VERSION 5.7 ;
  NOWIREEXTENSIONATPIN ON ;
  DIVIDERCHAR "/" ;
  BUSBITCHARS "[]" ;
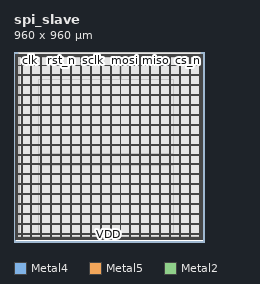
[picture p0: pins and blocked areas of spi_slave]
MACRO spi_slave
  CLASS BLOCK ;
  FOREIGN spi_slave ;
  ORIGIN 0.000 0.000 ;
  SIZE 960.000 BY 960.000 ;
  PIN VDD
    DIRECTION INOUT ;
    USE POWER ;
    PORT
      LAYER Metal4 ;
        RECT 14.160 17.520 19.160 942.880 ;
    END
    PORT
      LAYER Metal4 ;
        RECT 940.680 17.520 945.680 942.880 ;
    END
    PORT
      LAYER Metal5 ;
        RECT 14.160 17.520 945.680 22.520 ;
    END
    PORT
      LAYER Metal5 ;
        RECT 14.160 937.880 945.680 942.880 ;
    END
    PORT
      LAYER Metal4 ;
        RECT 35.680 10.520 37.280 949.880 ;
    END
    PORT
      LAYER Metal4 ;
        RECT 85.680 10.520 87.280 949.880 ;
    END
    PORT
      LAYER Metal4 ;
        RECT 135.680 10.520 137.280 949.880 ;
    END
    PORT
      LAYER Metal4 ;
        RECT 185.680 10.520 187.280 949.880 ;
    END
    PORT
      LAYER Metal4 ;
        RECT 235.680 10.520 237.280 949.880 ;
    END
    PORT
      LAYER Metal4 ;
        RECT 285.680 10.520 287.280 949.880 ;
    END
    PORT
      LAYER Metal4 ;
        RECT 335.680 10.520 337.280 949.880 ;
    END
    PORT
      LAYER Metal4 ;
        RECT 385.680 10.520 387.280 949.880 ;
    END
    PORT
      LAYER Metal4 ;
        RECT 435.680 10.520 437.280 949.880 ;
    END
    PORT
      LAYER Metal4 ;
        RECT 485.680 10.520 487.280 949.880 ;
    END
    PORT
      LAYER Metal4 ;
        RECT 535.680 10.520 537.280 949.880 ;
    END
    PORT
      LAYER Metal4 ;
        RECT 585.680 10.520 587.280 949.880 ;
    END
    PORT
      LAYER Metal4 ;
        RECT 635.680 10.520 637.280 949.880 ;
    END
    PORT
      LAYER Metal4 ;
        RECT 685.680 10.520 687.280 949.880 ;
    END
    PORT
      LAYER Metal4 ;
        RECT 735.680 10.520 737.280 949.880 ;
    END
    PORT
      LAYER Metal4 ;
        RECT 785.680 10.520 787.280 949.880 ;
    END
    PORT
      LAYER Metal4 ;
        RECT 835.680 10.520 837.280 949.880 ;
    END
    PORT
      LAYER Metal4 ;
        RECT 885.680 10.520 887.280 949.880 ;
    END
    PORT
      LAYER Metal4 ;
        RECT 935.680 10.520 937.280 949.880 ;
    END
    PORT
      LAYER Metal5 ;
        RECT 7.160 39.370 952.680 40.970 ;
    END
    PORT
      LAYER Metal5 ;
        RECT 7.160 89.370 952.680 90.970 ;
    END
    PORT
      LAYER Metal5 ;
        RECT 7.160 139.370 952.680 140.970 ;
    END
    PORT
      LAYER Metal5 ;
        RECT 7.160 189.370 952.680 190.970 ;
    END
    PORT
      LAYER Metal5 ;
        RECT 7.160 239.370 952.680 240.970 ;
    END
    PORT
      LAYER Metal5 ;
        RECT 7.160 289.370 952.680 290.970 ;
    END
    PORT
      LAYER Metal5 ;
        RECT 7.160 339.370 952.680 340.970 ;
    END
    PORT
      LAYER Metal5 ;
        RECT 7.160 389.370 952.680 390.970 ;
    END
    PORT
      LAYER Metal5 ;
        RECT 7.160 439.370 952.680 440.970 ;
    END
    PORT
      LAYER Metal5 ;
        RECT 7.160 489.370 952.680 490.970 ;
    END
    PORT
      LAYER Metal5 ;
        RECT 7.160 539.370 952.680 540.970 ;
    END
    PORT
      LAYER Metal5 ;
        RECT 7.160 589.370 952.680 590.970 ;
    END
    PORT
      LAYER Metal5 ;
        RECT 7.160 639.370 952.680 640.970 ;
    END
    PORT
      LAYER Metal5 ;
        RECT 7.160 689.370 952.680 690.970 ;
    END
    PORT
      LAYER Metal5 ;
        RECT 7.160 739.370 952.680 740.970 ;
    END
    PORT
      LAYER Metal5 ;
        RECT 7.160 789.370 952.680 790.970 ;
    END
    PORT
      LAYER Metal5 ;
        RECT 7.160 839.370 952.680 840.970 ;
    END
    PORT
      LAYER Metal5 ;
        RECT 7.160 889.370 952.680 890.970 ;
    END
  END VDD
  PIN VSS
    DIRECTION INOUT ;
    USE GROUND ;
    PORT
      LAYER Metal4 ;
        RECT 7.160 10.520 12.160 949.880 ;
    END
    PORT
      LAYER Metal4 ;
        RECT 947.680 10.520 952.680 949.880 ;
    END
    PORT
      LAYER Metal5 ;
        RECT 7.160 10.520 952.680 15.520 ;
    END
    PORT
      LAYER Metal5 ;
        RECT 7.160 944.880 952.680 949.880 ;
    END
    PORT
      LAYER Metal4 ;
        RECT 38.880 10.520 40.480 949.880 ;
    END
    PORT
      LAYER Metal4 ;
        RECT 88.880 10.520 90.480 949.880 ;
    END
    PORT
      LAYER Metal4 ;
        RECT 138.880 10.520 140.480 949.880 ;
    END
    PORT
      LAYER Metal4 ;
        RECT 188.880 10.520 190.480 949.880 ;
    END
    PORT
      LAYER Metal4 ;
        RECT 238.880 10.520 240.480 949.880 ;
    END
    PORT
      LAYER Metal4 ;
        RECT 288.880 10.520 290.480 949.880 ;
    END
    PORT
      LAYER Metal4 ;
        RECT 338.880 10.520 340.480 949.880 ;
    END
    PORT
      LAYER Metal4 ;
        RECT 388.880 10.520 390.480 949.880 ;
    END
    PORT
      LAYER Metal4 ;
        RECT 438.880 10.520 440.480 949.880 ;
    END
    PORT
      LAYER Metal4 ;
        RECT 488.880 10.520 490.480 949.880 ;
    END
    PORT
      LAYER Metal4 ;
        RECT 538.880 10.520 540.480 949.880 ;
    END
    PORT
      LAYER Metal4 ;
        RECT 588.880 10.520 590.480 949.880 ;
    END
    PORT
      LAYER Metal4 ;
        RECT 638.880 10.520 640.480 949.880 ;
    END
    PORT
      LAYER Metal4 ;
        RECT 688.880 10.520 690.480 949.880 ;
    END
    PORT
      LAYER Metal4 ;
        RECT 738.880 10.520 740.480 949.880 ;
    END
    PORT
      LAYER Metal4 ;
        RECT 788.880 10.520 790.480 949.880 ;
    END
    PORT
      LAYER Metal4 ;
        RECT 838.880 10.520 840.480 949.880 ;
    END
    PORT
      LAYER Metal4 ;
        RECT 888.880 10.520 890.480 949.880 ;
    END
    PORT
      LAYER Metal5 ;
        RECT 7.160 42.570 952.680 44.170 ;
    END
    PORT
      LAYER Metal5 ;
        RECT 7.160 92.570 952.680 94.170 ;
    END
    PORT
      LAYER Metal5 ;
        RECT 7.160 142.570 952.680 144.170 ;
    END
    PORT
      LAYER Metal5 ;
        RECT 7.160 192.570 952.680 194.170 ;
    END
    PORT
      LAYER Metal5 ;
        RECT 7.160 242.570 952.680 244.170 ;
    END
    PORT
      LAYER Metal5 ;
        RECT 7.160 292.570 952.680 294.170 ;
    END
    PORT
      LAYER Metal5 ;
        RECT 7.160 342.570 952.680 344.170 ;
    END
    PORT
      LAYER Metal5 ;
        RECT 7.160 392.570 952.680 394.170 ;
    END
    PORT
      LAYER Metal5 ;
        RECT 7.160 442.570 952.680 444.170 ;
    END
    PORT
      LAYER Metal5 ;
        RECT 7.160 492.570 952.680 494.170 ;
    END
    PORT
      LAYER Metal5 ;
        RECT 7.160 542.570 952.680 544.170 ;
    END
    PORT
      LAYER Metal5 ;
        RECT 7.160 592.570 952.680 594.170 ;
    END
    PORT
      LAYER Metal5 ;
        RECT 7.160 642.570 952.680 644.170 ;
    END
    PORT
      LAYER Metal5 ;
        RECT 7.160 692.570 952.680 694.170 ;
    END
    PORT
      LAYER Metal5 ;
        RECT 7.160 742.570 952.680 744.170 ;
    END
    PORT
      LAYER Metal5 ;
        RECT 7.160 792.570 952.680 794.170 ;
    END
    PORT
      LAYER Metal5 ;
        RECT 7.160 842.570 952.680 844.170 ;
    END
    PORT
      LAYER Metal5 ;
        RECT 7.160 892.570 952.680 894.170 ;
    END
  END VSS
  PIN clk
    DIRECTION INPUT ;
    USE SIGNAL ;
    ANTENNAGATEAREA 1.183000 ;
    ANTENNADIFFAREA 0.410400 ;
    PORT
      LAYER Metal2 ;
        RECT 81.760 959.440 82.320 960.000 ;
    END
  END clk
  PIN cs_n
    DIRECTION INPUT ;
    USE SIGNAL ;
    ANTENNAGATEAREA 0.741000 ;
    ANTENNADIFFAREA 0.410400 ;
    PORT
      LAYER Metal2 ;
        RECT 876.960 959.440 877.520 960.000 ;
    END
  END cs_n
  PIN miso
    DIRECTION OUTPUT ;
    USE SIGNAL ;
    ANTENNADIFFAREA 0.897600 ;
    PORT
      LAYER Metal2 ;
        RECT 717.920 959.440 718.480 960.000 ;
    END
  END miso
  PIN mosi
    DIRECTION INPUT ;
    USE SIGNAL ;
    ANTENNAGATEAREA 0.741000 ;
    ANTENNADIFFAREA 0.410400 ;
    PORT
      LAYER Metal2 ;
        RECT 558.880 959.440 559.440 960.000 ;
    END
  END mosi
  PIN rst_n
    DIRECTION INPUT ;
    USE SIGNAL ;
    ANTENNAGATEAREA 0.498500 ;
    ANTENNADIFFAREA 0.410400 ;
    PORT
      LAYER Metal2 ;
        RECT 240.800 959.440 241.360 960.000 ;
    END
  END rst_n
  PIN sclk
    DIRECTION INPUT ;
    USE SIGNAL ;
    ANTENNAGATEAREA 1.183000 ;
    ANTENNADIFFAREA 0.410400 ;
    PORT
      LAYER Metal2 ;
        RECT 399.840 959.440 400.400 960.000 ;
    END
  END sclk
  OBS
      LAYER Nwell ;
        RECT 19.730 23.090 940.110 937.310 ;
      LAYER Metal1 ;
        RECT 20.160 23.220 939.680 937.180 ;
      LAYER Metal2 ;
        RECT 21.980 959.140 81.460 959.860 ;
        RECT 82.620 959.140 240.500 959.860 ;
        RECT 241.660 959.140 399.540 959.860 ;
        RECT 400.700 959.140 558.580 959.860 ;
        RECT 559.740 959.140 717.620 959.860 ;
        RECT 718.780 959.140 876.660 959.860 ;
        RECT 877.820 959.140 940.100 959.860 ;
        RECT 21.980 23.330 940.100 959.140 ;
      LAYER Metal3 ;
        RECT 21.930 23.380 940.150 959.700 ;
      LAYER Metal4 ;
        RECT 25.340 25.850 35.380 930.630 ;
        RECT 37.580 25.850 38.580 930.630 ;
        RECT 40.780 25.850 85.380 930.630 ;
        RECT 87.580 25.850 88.580 930.630 ;
        RECT 90.780 25.850 135.380 930.630 ;
        RECT 137.580 25.850 138.580 930.630 ;
        RECT 140.780 25.850 185.380 930.630 ;
        RECT 187.580 25.850 188.580 930.630 ;
        RECT 190.780 25.850 235.380 930.630 ;
        RECT 237.580 25.850 238.580 930.630 ;
        RECT 240.780 25.850 285.380 930.630 ;
        RECT 287.580 25.850 288.580 930.630 ;
        RECT 290.780 25.850 335.380 930.630 ;
        RECT 337.580 25.850 338.580 930.630 ;
        RECT 340.780 25.850 385.380 930.630 ;
        RECT 387.580 25.850 388.580 930.630 ;
        RECT 390.780 25.850 435.380 930.630 ;
        RECT 437.580 25.850 438.580 930.630 ;
        RECT 440.780 25.850 485.380 930.630 ;
        RECT 487.580 25.850 488.580 930.630 ;
        RECT 490.780 25.850 535.380 930.630 ;
        RECT 537.580 25.850 538.580 930.630 ;
        RECT 540.780 25.850 585.380 930.630 ;
        RECT 587.580 25.850 588.580 930.630 ;
        RECT 590.780 25.850 635.380 930.630 ;
        RECT 637.580 25.850 638.580 930.630 ;
        RECT 640.780 25.850 685.380 930.630 ;
        RECT 687.580 25.850 688.580 930.630 ;
        RECT 690.780 25.850 735.380 930.630 ;
        RECT 737.580 25.850 738.580 930.630 ;
        RECT 740.780 25.850 785.380 930.630 ;
        RECT 787.580 25.850 788.580 930.630 ;
        RECT 790.780 25.850 835.380 930.630 ;
        RECT 837.580 25.850 838.580 930.630 ;
        RECT 840.780 25.850 885.380 930.630 ;
        RECT 887.580 25.850 888.580 930.630 ;
        RECT 890.780 25.850 935.380 930.630 ;
        RECT 937.580 25.850 937.860 930.630 ;
      LAYER Metal5 ;
        RECT 122.700 794.770 805.220 823.270 ;
        RECT 122.700 791.570 805.220 791.970 ;
        RECT 122.700 744.770 805.220 788.770 ;
        RECT 122.700 741.570 805.220 741.970 ;
        RECT 122.700 694.770 805.220 738.770 ;
        RECT 122.700 691.570 805.220 691.970 ;
        RECT 122.700 644.770 805.220 688.770 ;
        RECT 122.700 641.570 805.220 641.970 ;
        RECT 122.700 594.770 805.220 638.770 ;
        RECT 122.700 591.570 805.220 591.970 ;
        RECT 122.700 544.770 805.220 588.770 ;
        RECT 122.700 541.570 805.220 541.970 ;
        RECT 122.700 494.770 805.220 538.770 ;
        RECT 122.700 491.570 805.220 491.970 ;
        RECT 122.700 444.770 805.220 488.770 ;
        RECT 122.700 441.570 805.220 441.970 ;
        RECT 122.700 394.770 805.220 438.770 ;
        RECT 122.700 391.570 805.220 391.970 ;
        RECT 122.700 344.770 805.220 388.770 ;
        RECT 122.700 341.570 805.220 341.970 ;
        RECT 122.700 294.770 805.220 338.770 ;
        RECT 122.700 291.570 805.220 291.970 ;
        RECT 122.700 244.770 805.220 288.770 ;
        RECT 122.700 241.570 805.220 241.970 ;
        RECT 122.700 194.770 805.220 238.770 ;
        RECT 122.700 191.570 805.220 191.970 ;
        RECT 122.700 144.770 805.220 188.770 ;
        RECT 122.700 141.570 805.220 141.970 ;
        RECT 122.700 94.770 805.220 138.770 ;
        RECT 122.700 91.570 805.220 91.970 ;
        RECT 122.700 44.770 805.220 88.770 ;
        RECT 122.700 41.570 805.220 41.970 ;
        RECT 122.700 37.130 805.220 38.770 ;
  END
END spi_slave
END LIBRARY

